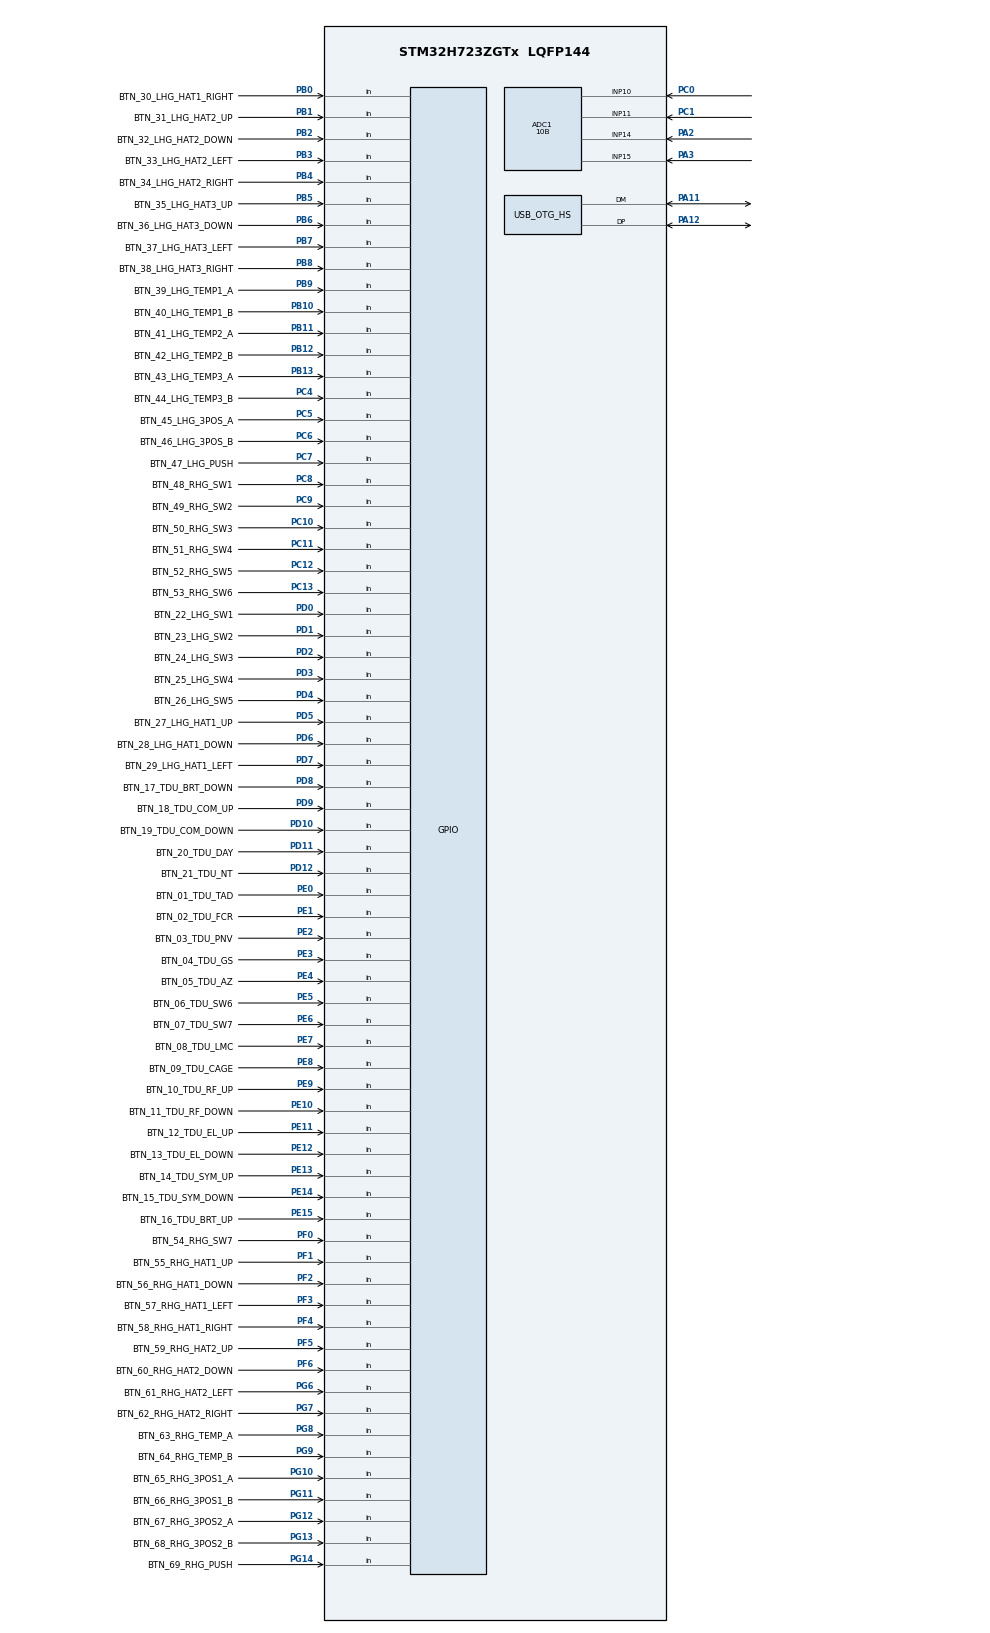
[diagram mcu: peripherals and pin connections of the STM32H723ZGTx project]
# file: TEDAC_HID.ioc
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ADC1.Channel-0\#ChannelRegularConversion=ADC_CHANNEL_3
ADC1.Channel-1\#ChannelRegularConversion=ADC_CHANNEL_7
ADC1.Channel-2\#ChannelRegularConversion=ADC_CHANNEL_14
ADC1.Channel-3\#ChannelRegularConversion=ADC_CHANNEL_15
ADC1.Channel-4\#ChannelRegularConversion=ADC_CHANNEL_10
ADC1.Channel-5\#ChannelRegularConversion=ADC_CHANNEL_11
ADC1.ClockPrescaler=ADC_CLOCK_ASYNC_DIV2
ADC1.ContinuousConvMode=ENABLE
ADC1.EOCSelection=ADC_EOC_SEQ_CONV
ADC1.ConversionDataManagement=ADC_CONVERSIONDATA_DMA_CIRCULAR
ADC1.Overrun=ADC_OVR_DATA_OVERWRITTEN
ADC1.NbrOfConversionFlag=6
ADC1.Rank-0\#ChannelRegularConversion=1
ADC1.Rank-1\#ChannelRegularConversion=2
ADC1.Rank-2\#ChannelRegularConversion=3
ADC1.Rank-3\#ChannelRegularConversion=4
ADC1.Rank-4\#ChannelRegularConversion=5
ADC1.Rank-5\#ChannelRegularConversion=6
ADC1.Resolution=ADC_RESOLUTION_10B
ADC1.ScanConvMode=ADC_SCAN_ENABLE
ADC1.SamplingTime-0\#ChannelRegularConversion=ADC_SAMPLETIME_387CYCLES_5
ADC1.SamplingTime-1\#ChannelRegularConversion=ADC_SAMPLETIME_387CYCLES_5
ADC1.SamplingTime-2\#ChannelRegularConversion=ADC_SAMPLETIME_387CYCLES_5
ADC1.SamplingTime-3\#ChannelRegularConversion=ADC_SAMPLETIME_387CYCLES_5
ADC1.SamplingTime-4\#ChannelRegularConversion=ADC_SAMPLETIME_387CYCLES_5
ADC1.SamplingTime-5\#ChannelRegularConversion=ADC_SAMPLETIME_387CYCLES_5
ADC1.master=1
CORTEX_M7.default_mode_Activation=1
Dma.ADC1.0.Direction=DMA_PERIPH_TO_MEMORY
Dma.ADC1.0.EventEnable=DISABLE
Dma.ADC1.0.FIFOMode=DMA_FIFOMODE_DISABLE
Dma.ADC1.0.Instance=DMA1_Stream0
Dma.ADC1.0.MemDataAlignment=DMA_MDATAALIGN_HALFWORD
Dma.ADC1.0.MemInc=DMA_MINC_ENABLE
Dma.ADC1.0.Mode=DMA_CIRCULAR
Dma.ADC1.0.PeriphDataAlignment=DMA_PDATAALIGN_HALFWORD
Dma.ADC1.0.PeriphInc=DMA_PINC_DISABLE
Dma.ADC1.0.Polarity=HAL_DMAMUX_REQ_GEN_RISING
Dma.ADC1.0.Priority=DMA_PRIORITY_LOW
Dma.ADC1.0.RequestNumber=1
Dma.ADC1.0.SignalID=NONE
Dma.ADC1.0.SyncEnable=DISABLE
Dma.ADC1.0.SyncPolarity=HAL_DMAMUX_SYNC_NO_EVENT
Dma.ADC1.0.SyncRequestNumber=1
Dma.ADC1.0.SyncSignalID=NONE
Dma.Request0=ADC1
Mcu.Family=STM32H7
Mcu.Name=STM32H723ZGTx
Mcu.Package=LQFP144
NVIC.DMA1_Stream0_IRQn=true\:0\:0\:false\:false\:true\:false\:true\:true
NVIC.OTG_HS_EP1_IN_IRQn=true\:0\:0\:false\:false\:true\:true\:true\:true
NVIC.OTG_HS_EP1_OUT_IRQn=true\:0\:0\:false\:false\:true\:true\:true\:true
NVIC.OTG_HS_IRQn=true\:0\:0\:false\:false\:true\:true\:true\:true
NVIC.PriorityGroup=NVIC_PRIORITYGROUP_4
NVIC.TIM15_IRQn=true\:0\:0\:false\:false\:true\:true\:true\:true
PA11.Mode=Device_Only_FS
PA11.Signal=USB_OTG_HS_DM
PA12.Mode=Device_Only_FS
PA12.Signal=USB_OTG_HS_DP
PA2.Signal=ADCx_INP14
PA3.Signal=ADCx_INP15
PA6.Signal=ADCx_INP3
PA7.Signal=ADCx_INP7
PB0.GPIO_Label=BTN_30_LHG_HAT1_RIGHT
PB0.GPIO_PuPd=GPIO_PULLUP
PB0.Signal=GPIO_Input
PB1.GPIO_Label=BTN_31_LHG_HAT2_UP
PB1.GPIO_PuPd=GPIO_PULLUP
PB1.Signal=GPIO_Input
PB10.GPIO_Label=BTN_40_LHG_TEMP1_B
PB10.GPIO_PuPd=GPIO_PULLUP
PB10.Signal=GPIO_Input
PB11.GPIO_Label=BTN_41_LHG_TEMP2_A
PB11.GPIO_PuPd=GPIO_PULLUP
PB11.Signal=GPIO_Input
PB12.GPIO_Label=BTN_42_LHG_TEMP2_B
PB12.GPIO_PuPd=GPIO_PULLUP
PB12.Signal=GPIO_Input
PB13.GPIO_Label=BTN_43_LHG_TEMP3_A
PB13.GPIO_PuPd=GPIO_PULLUP
PB13.Signal=GPIO_Input
PB2.GPIO_Label=BTN_32_LHG_HAT2_DOWN
PB2.GPIO_PuPd=GPIO_PULLUP
PB2.Signal=GPIO_Input
PB3(JTDO/TRACESWO).GPIO_Label=BTN_33_LHG_HAT2_LEFT
PB3(JTDO/TRACESWO).GPIO_PuPd=GPIO_PULLUP
PB3(JTDO/TRACESWO).Signal=GPIO_Input
PB4(NJTRST).GPIO_Label=BTN_34_LHG_HAT2_RIGHT
PB4(NJTRST).GPIO_PuPd=GPIO_PULLUP
PB4(NJTRST).Signal=GPIO_Input
PB5.GPIO_Label=BTN_35_LHG_HAT3_UP
PB5.GPIO_PuPd=GPIO_PULLUP
PB5.Signal=GPIO_Input
PB6.GPIO_Label=BTN_36_LHG_HAT3_DOWN
PB6.GPIO_PuPd=GPIO_PULLUP
PB6.Signal=GPIO_Input
PB7.GPIO_Label=BTN_37_LHG_HAT3_LEFT
PB7.GPIO_PuPd=GPIO_PULLUP
PB7.Signal=GPIO_Input
PB8.GPIO_Label=BTN_38_LHG_HAT3_RIGHT
PB8.GPIO_PuPd=GPIO_PULLUP
PB8.Signal=GPIO_Input
PB9.GPIO_Label=BTN_39_LHG_TEMP1_A
PB9.GPIO_PuPd=GPIO_PULLUP
PB9.Signal=GPIO_Input
PC0.Signal=ADCx_INP10
PC1.Signal=ADCx_INP11
PC10.GPIO_Label=BTN_50_RHG_SW3
PC10.GPIO_PuPd=GPIO_PULLUP
PC10.Signal=GPIO_Input
PC11.GPIO_Label=BTN_51_RHG_SW4
PC11.GPIO_PuPd=GPIO_PULLUP
PC11.Signal=GPIO_Input
PC12.GPIO_Label=BTN_52_RHG_SW5
PC12.GPIO_PuPd=GPIO_PULLUP
PC12.Signal=GPIO_Input
PC13.GPIO_Label=BTN_53_RHG_SW6
PC13.GPIO_PuPd=GPIO_PULLUP
PC13.Signal=GPIO_Input
PC4.GPIO_Label=BTN_44_LHG_TEMP3_B
PC4.GPIO_PuPd=GPIO_PULLUP
PC4.Signal=GPIO_Input
PC5.GPIO_Label=BTN_45_LHG_3POS_A
PC5.GPIO_PuPd=GPIO_PULLUP
PC5.Signal=GPIO_Input
PC6.GPIO_Label=BTN_46_LHG_3POS_B
PC6.GPIO_PuPd=GPIO_PULLUP
PC6.Signal=GPIO_Input
PC7.GPIO_Label=BTN_47_LHG_PUSH
PC7.GPIO_PuPd=GPIO_PULLUP
PC7.Signal=GPIO_Input
PC8.GPIO_Label=BTN_48_RHG_SW1
PC8.GPIO_PuPd=GPIO_PULLUP
PC8.Signal=GPIO_Input
PC9.GPIO_Label=BTN_49_RHG_SW2
PC9.GPIO_PuPd=GPIO_PULLUP
PC9.Signal=GPIO_Input
PD0.GPIO_Label=BTN_22_LHG_SW1
PD0.GPIO_PuPd=GPIO_PULLUP
PD0.Signal=GPIO_Input
PD1.GPIO_Label=BTN_23_LHG_SW2
PD1.GPIO_PuPd=GPIO_PULLUP
PD1.Signal=GPIO_Input
PD10.GPIO_Label=BTN_19_TDU_COM_DOWN
PD10.GPIO_PuPd=GPIO_PULLUP
PD10.Signal=GPIO_Input
PD11.GPIO_Label=BTN_20_TDU_DAY
PD11.GPIO_PuPd=GPIO_PULLUP
PD11.Signal=GPIO_Input
PD12.GPIO_Label=BTN_21_TDU_NT
PD12.GPIO_PuPd=GPIO_PULLUP
PD12.Signal=GPIO_Input
PD2.GPIO_Label=BTN_24_LHG_SW3
PD2.GPIO_PuPd=GPIO_PULLUP
PD2.Signal=GPIO_Input
PD3.GPIO_Label=BTN_25_LHG_SW4
PD3.GPIO_PuPd=GPIO_PULLUP
PD3.Signal=GPIO_Input
PD4.GPIO_Label=BTN_26_LHG_SW5
PD4.GPIO_PuPd=GPIO_PULLUP
PD4.Signal=GPIO_Input
PD5.GPIO_Label=BTN_27_LHG_HAT1_UP
PD5.GPIO_PuPd=GPIO_PULLUP
PD5.Signal=GPIO_Input
PD6.GPIO_Label=BTN_28_LHG_HAT1_DOWN
PD6.GPIO_PuPd=GPIO_PULLUP
PD6.Signal=GPIO_Input
PD7.GPIO_Label=BTN_29_LHG_HAT1_LEFT
PD7.GPIO_PuPd=GPIO_PULLUP
PD7.Signal=GPIO_Input
PD8.GPIO_Label=BTN_17_TDU_BRT_DOWN
PD8.GPIO_PuPd=GPIO_PULLUP
PD8.Signal=GPIO_Input
PD9.GPIO_Label=BTN_18_TDU_COM_UP
PD9.GPIO_PuPd=GPIO_PULLUP
PD9.Signal=GPIO_Input
PE0.GPIO_Label=BTN_01_TDU_TAD
PE0.GPIO_PuPd=GPIO_PULLUP
PE0.Signal=GPIO_Input
PE1.GPIO_Label=BTN_02_TDU_FCR
PE1.GPIO_PuPd=GPIO_PULLUP
PE1.Signal=GPIO_Input
PE10.GPIO_Label=BTN_11_TDU_RF_DOWN
PE10.GPIO_PuPd=GPIO_PULLUP
PE10.Signal=GPIO_Input
PE11.GPIO_Label=BTN_12_TDU_EL_UP
PE11.GPIO_PuPd=GPIO_PULLUP
PE11.Signal=GPIO_Input
PE12.GPIO_Label=BTN_13_TDU_EL_DOWN
PE12.GPIO_PuPd=GPIO_PULLUP
PE12.Signal=GPIO_Input
PE13.GPIO_Label=BTN_14_TDU_SYM_UP
PE13.GPIO_PuPd=GPIO_PULLUP
PE13.Signal=GPIO_Input
PE14.GPIO_Label=BTN_15_TDU_SYM_DOWN
PE14.GPIO_PuPd=GPIO_PULLUP
PE14.Signal=GPIO_Input
PE15.GPIO_Label=BTN_16_TDU_BRT_UP
PE15.GPIO_PuPd=GPIO_PULLUP
PE15.Signal=GPIO_Input
PE2.GPIO_Label=BTN_03_TDU_PNV
PE2.GPIO_PuPd=GPIO_PULLUP
PE2.Signal=GPIO_Input
PE3.GPIO_Label=BTN_04_TDU_GS
PE3.GPIO_PuPd=GPIO_PULLUP
PE3.Signal=GPIO_Input
PE4.GPIO_Label=BTN_05_TDU_AZ
PE4.GPIO_PuPd=GPIO_PULLUP
PE4.Signal=GPIO_Input
PE5.GPIO_Label=BTN_06_TDU_SW6
PE5.GPIO_PuPd=GPIO_PULLUP
PE5.Signal=GPIO_Input
PE6.GPIO_Label=BTN_07_TDU_SW7
PE6.GPIO_PuPd=GPIO_PULLUP
PE6.Signal=GPIO_Input
PE7.GPIO_Label=BTN_08_TDU_LMC
PE7.GPIO_PuPd=GPIO_PULLUP
PE7.Signal=GPIO_Input
PE8.GPIO_Label=BTN_09_TDU_CAGE
PE8.GPIO_PuPd=GPIO_PULLUP
PE8.Signal=GPIO_Input
PE9.GPIO_Label=BTN_10_TDU_RF_UP
PE9.GPIO_PuPd=GPIO_PULLUP
PE9.Signal=GPIO_Input
PF0.GPIO_Label=BTN_54_RHG_SW7
PF0.GPIO_PuPd=GPIO_PULLUP
PF0.Signal=GPIO_Input
PF1.GPIO_Label=BTN_55_RHG_HAT1_UP
PF1.GPIO_PuPd=GPIO_PULLUP
PF1.Signal=GPIO_Input
PF2.GPIO_Label=BTN_56_RHG_HAT1_DOWN
PF2.GPIO_PuPd=GPIO_PULLUP
PF2.Signal=GPIO_Input
PF3.GPIO_Label=BTN_57_RHG_HAT1_LEFT
PF3.GPIO_PuPd=GPIO_PULLUP
PF3.Signal=GPIO_Input
PF4.GPIO_Label=BTN_58_RHG_HAT1_RIGHT
PF4.GPIO_PuPd=GPIO_PULLUP
PF4.Signal=GPIO_Input
PF5.GPIO_Label=BTN_59_RHG_HAT2_UP
PF5.GPIO_PuPd=GPIO_PULLUP
PF5.Signal=GPIO_Input
PF6.GPIO_Label=BTN_60_RHG_HAT2_DOWN
PF6.GPIO_PuPd=GPIO_PULLUP
PF6.Signal=GPIO_Input
PG10.GPIO_Label=BTN_65_RHG_3POS1_A
PG10.GPIO_PuPd=GPIO_PULLUP
PG10.Signal=GPIO_Input
PG11.GPIO_Label=BTN_66_RHG_3POS1_B
PG11.GPIO_PuPd=GPIO_PULLUP
PG11.Signal=GPIO_Input
PG12.GPIO_Label=BTN_67_RHG_3POS2_A
PG12.GPIO_PuPd=GPIO_PULLUP
PG12.Signal=GPIO_Input
PG13.GPIO_Label=BTN_68_RHG_3POS2_B
PG13.GPIO_PuPd=GPIO_PULLUP
PG13.Signal=GPIO_Input
PG14.GPIO_Label=BTN_69_RHG_PUSH
PG14.GPIO_PuPd=GPIO_PULLUP
PG14.Signal=GPIO_Input
PG6.GPIO_Label=BTN_61_RHG_HAT2_LEFT
PG6.GPIO_PuPd=GPIO_PULLUP
PG6.Signal=GPIO_Input
PG7.GPIO_Label=BTN_62_RHG_HAT2_RIGHT
PG7.GPIO_PuPd=GPIO_PULLUP
PG7.Signal=GPIO_Input
PG8.GPIO_Label=BTN_63_RHG_TEMP_A
PG8.GPIO_PuPd=GPIO_PULLUP
PG8.Signal=GPIO_Input
PG9.GPIO_Label=BTN_64_RHG_TEMP_B
PG9.GPIO_PuPd=GPIO_PULLUP
PG9.Signal=GPIO_Input
PH0-OSC_IN.Mode=HSE-External-Oscillator
PH0-OSC_IN.Signal=RCC_OSC_IN
PH1-OSC_OUT.Mode=HSE-External-Oscillator
PH1-OSC_OUT.Signal=RCC_OSC_OUT
ProjectManager.HeapSize=0x200
ProjectManager.StackSize=0x400
ProjectManager.TargetToolchain=STM32CubeIDE
RCC.ADCFreq_Value=20000000
RCC.APB1Freq_Value=137500000
RCC.APB2Freq_Value=137500000
RCC.APB3Freq_Value=137500000
RCC.APB4Freq_Value=137500000
RCC.CortexFreq_Value=275000000
RCC.D1PPRE=RCC_APB3_DIV2
RCC.D2PPRE1=RCC_APB1_DIV2
RCC.D2PPRE2=RCC_APB2_DIV2
RCC.D3PPRE=RCC_APB4_DIV2
RCC.DIVM1=2
RCC.DIVM2=2
RCC.DIVM3=2
RCC.DIVN1=22
RCC.DIVN2=40
RCC.DIVN3=24
RCC.DIVP1=1
RCC.DIVP2=25
RCC.DIVQ1=5
RCC.DIVQ3=5
RCC.HCLKFreq_Value=275000000
RCC.PLL2FRACN=0
RCC.PLL3FRACN=0
RCC.PLLFRACN=0
RCC.PLLSourceVirtual=RCC_PLLSOURCE_HSE
RCC.SYSCLKFreq_VALUE=275000000
RCC.SYSCLKSource=RCC_SYSCLKSOURCE_PLLCLK
RCC.USBCLockSelection=RCC_USBCLKSOURCE_HSI48
RCC.USBFreq_Value=48000000
SH.ADCx_INP10.0=ADC1_INP10,IN10-Single-Ended
SH.ADCx_INP11.0=ADC1_INP11,IN11-Single-Ended
SH.ADCx_INP14.0=ADC1_INP14,IN14-Single-Ended
SH.ADCx_INP15.0=ADC1_INP15,IN15-Single-Ended
SH.ADCx_INP3.0=ADC1_INP3
SH.ADCx_INP7.0=ADC1_INP7
TIM15.Period=100-1
TIM15.Prescaler=2750-1
TIM15.TIM_MasterOutputTrigger=TIM_TRGO_UPDATE
USB_DEVICE.CLASS_NAME_HS=CUSTOM_HID
USB_DEVICE.MANUFACTURER_STRING=DIPRE
USB_DEVICE.PRODUCT_STRING_CUSTOMHID_HS=TEDAC AH-64D
USB_DEVICE.USBD_CUSTOM_HID_REPORT_DESC_SIZE=0x37
USB_DEVICE.VirtualMode=CustomHid
USB_DEVICE.VirtualModeHS=Custom_Hid_HS
USB_OTG_HS.VirtualMode-Device_Only_FS=Device_Only_FS
VP_MEMORYMAP_VS_MEMORYMAP.Mode=CurAppReg
VP_RCC_USB.Mode=USB_HS
VP_TIM15_VS_ClockSourceINT.Mode=Internal
VP_USB_DEVICE_VS_USB_DEVICE_CUSTOM_HID_HS.Mode=CUSTOM_HID_HS
board=custom

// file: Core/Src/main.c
/* USER CODE BEGIN Header */
/**
  ******************************************************************************
  * @file           : main.c
  * @brief          : Main program body
  ******************************************************************************
  * @attention
  *
  * Copyright (c) 2026 STMicroelectronics.
  * All rights reserved.
  *
  * This software is licensed under terms that can be found in the LICENSE file
  * in the root directory of this software component.
  * If no LICENSE file comes with this software, it is provided AS-IS.
  *
  ******************************************************************************
  */
/* USER CODE END Header */
#include "main.h"
#include "usb_device.h"

/* USER CODE BEGIN Includes */
#include "usbd_custom_hid_if.h"
/* USER CODE END Includes */

ADC_HandleTypeDef hadc1;
DMA_HandleTypeDef hdma_adc1;

TIM_HandleTypeDef htim15;

/* USER CODE BEGIN PV */
/*
 * CRITICAL: adc_buf MUST be in D2 SRAM (0x30000000) because DMA1 lives in the
 * D2 bus-matrix domain and CANNOT access D1 AXI SRAM (0x24000000 / RAM_D1).
 * Without this attribute the linker places it in .bss → RAM_D1 → DMA writes go nowhere.
 */
volatile uint16_t adc_buf[6] __attribute__((section(".RAM_D2")));
/* USER CODE END PV */

void SystemClock_Config(void);
static void MPU_Config(void);
static void MX_GPIO_Init(void);
static void MX_DMA_Init(void);
static void MX_ADC1_Init(void);
static void MX_TIM15_Init(void);

int main(void)
{

  /* MPU Configuration--------------------------------------------------------*/
  MPU_Config();

  /* MCU Configuration--------------------------------------------------------*/

  /* Reset of all peripherals, Initializes the Flash interface and the Systick. */
  HAL_Init();

  /* Configure the system clock */
  SystemClock_Config();

  /* Initialize all configured peripherals */
  MX_GPIO_Init();
  MX_DMA_Init();
  MX_ADC1_Init();
  MX_TIM15_Init();
  MX_USB_DEVICE_Init();
  /* USER CODE BEGIN 2 */
  if (HAL_ADCEx_Calibration_Start(&hadc1, ADC_CALIB_OFFSET, ADC_SINGLE_ENDED) != HAL_OK)
  {
    Error_Handler();
  }

  if (HAL_ADC_Start_DMA(&hadc1, (uint32_t*)adc_buf, 6) != HAL_OK)
  {
    Error_Handler();
  }

  if (HAL_TIM_Base_Start_IT(&htim15) != HAL_OK)
  {
    Error_Handler();
  }
  /* USER CODE END 2 */

  /* Infinite loop */
  while (1)
  {

  }
}

void SystemClock_Config(void)
{
  RCC_OscInitTypeDef RCC_OscInitStruct = {0};
  RCC_ClkInitTypeDef RCC_ClkInitStruct = {0};
  RCC_CRSInitTypeDef RCC_CRSInitStruct = {0};

  /** Supply configuration update enable
  */
  HAL_PWREx_ConfigSupply(PWR_LDO_SUPPLY);

  /** Configure the main internal regulator output voltage
  */
  __HAL_PWR_VOLTAGESCALING_CONFIG(PWR_REGULATOR_VOLTAGE_SCALE0);

  while(!__HAL_PWR_GET_FLAG(PWR_FLAG_VOSRDY)) {}

  /** Initializes the RCC Oscillators according to the specified parameters
  * in the RCC_OscInitTypeDef structure.
  */
  RCC_OscInitStruct.OscillatorType = RCC_OSCILLATORTYPE_HSI48|RCC_OSCILLATORTYPE_HSE;
  RCC_OscInitStruct.HSEState = RCC_HSE_ON;
  RCC_OscInitStruct.HSI48State = RCC_HSI48_ON;
  RCC_OscInitStruct.PLL.PLLState = RCC_PLL_ON;
  RCC_OscInitStruct.PLL.PLLSource = RCC_PLLSOURCE_HSE;
  RCC_OscInitStruct.PLL.PLLM = 2;
  RCC_OscInitStruct.PLL.PLLN = 22;
  RCC_OscInitStruct.PLL.PLLP = 1;
  RCC_OscInitStruct.PLL.PLLQ = 5;
  RCC_OscInitStruct.PLL.PLLR = 2;
  RCC_OscInitStruct.PLL.PLLRGE = RCC_PLL1VCIRANGE_3;
  RCC_OscInitStruct.PLL.PLLVCOSEL = RCC_PLL1VCOWIDE;
  RCC_OscInitStruct.PLL.PLLFRACN = 0;
  if (HAL_RCC_OscConfig(&RCC_OscInitStruct) != HAL_OK)
  {
    Error_Handler();
  }

  /** Initializes the CPU, AHB and APB buses clocks
  */
  RCC_ClkInitStruct.ClockType = RCC_CLOCKTYPE_HCLK|RCC_CLOCKTYPE_SYSCLK
                              |RCC_CLOCKTYPE_PCLK1|RCC_CLOCKTYPE_PCLK2
                              |RCC_CLOCKTYPE_D3PCLK1|RCC_CLOCKTYPE_D1PCLK1;
  RCC_ClkInitStruct.SYSCLKSource = RCC_SYSCLKSOURCE_PLLCLK;
  RCC_ClkInitStruct.SYSCLKDivider = RCC_SYSCLK_DIV1;
  RCC_ClkInitStruct.AHBCLKDivider = RCC_HCLK_DIV1;
  RCC_ClkInitStruct.APB3CLKDivider = RCC_APB3_DIV2;
  RCC_ClkInitStruct.APB1CLKDivider = RCC_APB1_DIV2;
  RCC_ClkInitStruct.APB2CLKDivider = RCC_APB2_DIV2;
  RCC_ClkInitStruct.APB4CLKDivider = RCC_APB4_DIV2;

  if (HAL_RCC_ClockConfig(&RCC_ClkInitStruct, FLASH_LATENCY_3) != HAL_OK)
  {
    Error_Handler();
  }

  /** Enable the SYSCFG APB clock
  */
  __HAL_RCC_CRS_CLK_ENABLE();

  /** Configures CRS
  */
  RCC_CRSInitStruct.Prescaler = RCC_CRS_SYNC_DIV1;
  RCC_CRSInitStruct.Source = RCC_CRS_SYNC_SOURCE_USB2;
  RCC_CRSInitStruct.Polarity = RCC_CRS_SYNC_POLARITY_RISING;
  RCC_CRSInitStruct.ReloadValue = __HAL_RCC_CRS_RELOADVALUE_CALCULATE(48000000,1000);
  RCC_CRSInitStruct.ErrorLimitValue = 34;
  RCC_CRSInitStruct.HSI48CalibrationValue = 32;

  HAL_RCCEx_CRSConfig(&RCC_CRSInitStruct);
}

static void MX_ADC1_Init(void)
{

  ADC_MultiModeTypeDef multimode = {0};
  ADC_ChannelConfTypeDef sConfig = {0};

  /** Common config
  */
  hadc1.Instance = ADC1;
  hadc1.Init.ClockPrescaler = ADC_CLOCK_ASYNC_DIV2;
  hadc1.Init.Resolution = ADC_RESOLUTION_10B;
  hadc1.Init.ScanConvMode = ADC_SCAN_ENABLE;        /* 6 channels */
  hadc1.Init.EOCSelection = ADC_EOC_SEQ_CONV;       /* end of sequence */
  hadc1.Init.LowPowerAutoWait = DISABLE;
  hadc1.Init.ContinuousConvMode = ENABLE;
  hadc1.Init.NbrOfConversion = 6;
  hadc1.Init.DiscontinuousConvMode = DISABLE;
  hadc1.Init.ExternalTrigConv = ADC_SOFTWARE_START;
  hadc1.Init.ExternalTrigConvEdge = ADC_EXTERNALTRIGCONVEDGE_NONE;
  hadc1.Init.ConversionDataManagement = ADC_CONVERSIONDATA_DMA_CIRCULAR;
  hadc1.Init.Overrun = ADC_OVR_DATA_OVERWRITTEN;
  hadc1.Init.LeftBitShift = ADC_LEFTBITSHIFT_NONE;
  hadc1.Init.OversamplingMode = DISABLE;
  hadc1.Init.Oversampling.Ratio = 1;
  if (HAL_ADC_Init(&hadc1) != HAL_OK)
  {
    Error_Handler();
  }

  /** Configure the ADC multi-mode
  */
  multimode.Mode = ADC_MODE_INDEPENDENT;
  if (HAL_ADCEx_MultiModeConfigChannel(&hadc1, &multimode) != HAL_OK)
  {
    Error_Handler();
  }

  /* Rank 1: IN3  = PA6  = X axis */
  sConfig.Channel = ADC_CHANNEL_3;
  sConfig.Rank = ADC_REGULAR_RANK_1;
  sConfig.SamplingTime = ADC_SAMPLETIME_387CYCLES_5;
  sConfig.SingleDiff = ADC_SINGLE_ENDED;
  sConfig.OffsetNumber = ADC_OFFSET_NONE;
  sConfig.Offset = 0;
  sConfig.OffsetSignedSaturation = DISABLE;
  if (HAL_ADC_ConfigChannel(&hadc1, &sConfig) != HAL_OK)
  {
    Error_Handler();
  }

  /* Rank 2: IN7  = PA7  = Y axis */
  sConfig.Channel = ADC_CHANNEL_7;
  sConfig.Rank = ADC_REGULAR_RANK_2;
  if (HAL_ADC_ConfigChannel(&hadc1, &sConfig) != HAL_OK)
  {
    Error_Handler();
  }

  /* Rank 3: IN14 = PA2  = Z axis */
  sConfig.Channel = ADC_CHANNEL_14;
  sConfig.Rank = ADC_REGULAR_RANK_3;
  if (HAL_ADC_ConfigChannel(&hadc1, &sConfig) != HAL_OK)
  {
    Error_Handler();
  }

  /* Rank 4: IN15 = PA3  = Rx axis */
  sConfig.Channel = ADC_CHANNEL_15;
  sConfig.Rank = ADC_REGULAR_RANK_4;
  if (HAL_ADC_ConfigChannel(&hadc1, &sConfig) != HAL_OK)
  {
    Error_Handler();
  }

  /* Rank 5: IN10 = PC0  = Ry axis */
  sConfig.Channel = ADC_CHANNEL_10;
  sConfig.Rank = ADC_REGULAR_RANK_5;
  if (HAL_ADC_ConfigChannel(&hadc1, &sConfig) != HAL_OK)
  {
    Error_Handler();
  }

  /* Rank 6: IN11 = PC1  = Rz axis */
  sConfig.Channel = ADC_CHANNEL_11;
  sConfig.Rank = ADC_REGULAR_RANK_6;
  if (HAL_ADC_ConfigChannel(&hadc1, &sConfig) != HAL_OK)
  {
    Error_Handler();
  }

  /* USER CODE BEGIN ADC1_Init 2 */

  /*
   * STM32H7 CRITICAL: PCSEL register must pre-select all channels before
   * starting conversions. Without this, the ADC samples floating inputs.
   * Bits correspond directly to channel numbers (bit N = channel N).
   */
  /* On STM32H723, ADC_TypeDef names this field PCSEL_RES0 (shared with ADC3
   * reservation), but it is the PCSEL register at offset 0x1C for ADC1/2. */
  ADC1->PCSEL_RES0 |= (1UL << 3)  /* IN3  = PA6 */
                    | (1UL << 7)  /* IN7  = PA7 */
                    | (1UL << 10) /* IN10 = PC0 */
                    | (1UL << 11) /* IN11 = PC1 */
                    | (1UL << 14) /* IN14 = PA2 */
                    | (1UL << 15);/* IN15 = PA3 */

  /* USER CODE END ADC1_Init 2 */

}

static void MX_TIM15_Init(void)
{

  TIM_ClockConfigTypeDef sClockSourceConfig = {0};
  TIM_MasterConfigTypeDef sMasterConfig = {0};

  htim15.Instance = TIM15;
  htim15.Init.Prescaler = 2750-1;
  htim15.Init.CounterMode = TIM_COUNTERMODE_UP;
  htim15.Init.Period = 100-1;
  htim15.Init.ClockDivision = TIM_CLOCKDIVISION_DIV1;
  htim15.Init.RepetitionCounter = 0;
  htim15.Init.AutoReloadPreload = TIM_AUTORELOAD_PRELOAD_DISABLE;
  if (HAL_TIM_Base_Init(&htim15) != HAL_OK)
  {
    Error_Handler();
  }
  sClockSourceConfig.ClockSource = TIM_CLOCKSOURCE_INTERNAL;
  if (HAL_TIM_ConfigClockSource(&htim15, &sClockSourceConfig) != HAL_OK)
  {
    Error_Handler();
  }
  sMasterConfig.MasterOutputTrigger = TIM_TRGO_UPDATE;
  sMasterConfig.MasterSlaveMode = TIM_MASTERSLAVEMODE_DISABLE;
  if (HAL_TIMEx_MasterConfigSynchronization(&htim15, &sMasterConfig) != HAL_OK)
  {
    Error_Handler();
  }

}

static void MX_DMA_Init(void)
{

  /* DMA controller clock enable */
  __HAL_RCC_DMA1_CLK_ENABLE();

  /* DMA interrupt init */
  /* DMA1_Stream0_IRQn interrupt configuration */
  HAL_NVIC_SetPriority(DMA1_Stream0_IRQn, 0, 0);
  HAL_NVIC_EnableIRQ(DMA1_Stream0_IRQn);

}

static void MX_GPIO_Init(void)
{
  GPIO_InitTypeDef GPIO_InitStruct = {0};

  /* GPIO Ports Clock Enable */
  __HAL_RCC_GPIOE_CLK_ENABLE();
  __HAL_RCC_GPIOC_CLK_ENABLE();
  __HAL_RCC_GPIOF_CLK_ENABLE();
  __HAL_RCC_GPIOH_CLK_ENABLE();
  __HAL_RCC_GPIOA_CLK_ENABLE();
  __HAL_RCC_GPIOB_CLK_ENABLE();
  __HAL_RCC_GPIOD_CLK_ENABLE();
  __HAL_RCC_GPIOG_CLK_ENABLE();

  /*Configure GPIO pins : BTN_03_TDU_PNV_Pin BTN_04_TDU_GS_Pin BTN_05_TDU_AZ_Pin BTN_06_TDU_SW6_Pin
                           BTN_07_TDU_SW7_Pin BTN_08_TDU_LMC_Pin BTN_09_TDU_CAGE_Pin BTN_10_TDU_RF_UP_Pin
                           BTN_11_TDU_RF_DOWN_Pin BTN_12_TDU_EL_UP_Pin BTN_13_TDU_EL_DOWN_Pin BTN_14_TDU_SYM_UP_Pin
                           BTN_15_TDU_SYM_DOWN_Pin BTN_16_TDU_BRT_UP_Pin BTN_01_TDU_TAD_Pin BTN_02_TDU_FCR_Pin */
  GPIO_InitStruct.Pin = BTN_03_TDU_PNV_Pin|BTN_04_TDU_GS_Pin|BTN_05_TDU_AZ_Pin|BTN_06_TDU_SW6_Pin
                          |BTN_07_TDU_SW7_Pin|BTN_08_TDU_LMC_Pin|BTN_09_TDU_CAGE_Pin|BTN_10_TDU_RF_UP_Pin
                          |BTN_11_TDU_RF_DOWN_Pin|BTN_12_TDU_EL_UP_Pin|BTN_13_TDU_EL_DOWN_Pin|BTN_14_TDU_SYM_UP_Pin
                          |BTN_15_TDU_SYM_DOWN_Pin|BTN_16_TDU_BRT_UP_Pin|BTN_01_TDU_TAD_Pin|BTN_02_TDU_FCR_Pin;
  GPIO_InitStruct.Mode = GPIO_MODE_INPUT;
  GPIO_InitStruct.Pull = GPIO_PULLUP;
  HAL_GPIO_Init(GPIOE, &GPIO_InitStruct);

  /*Configure GPIO pins : BTN_53_RHG_SW6_Pin BTN_44_LHG_TEMP3_B_Pin BTN_45_LHG_3POS_A_Pin BTN_46_LHG_3POS_B_Pin
                           BTN_47_LHG_PUSH_Pin BTN_50_RHG_SW3_Pin BTN_51_RHG_SW4_Pin BTN_52_RHG_SW5_Pin */
  GPIO_InitStruct.Pin = BTN_53_RHG_SW6_Pin|BTN_44_LHG_TEMP3_B_Pin|BTN_45_LHG_3POS_A_Pin|BTN_46_LHG_3POS_B_Pin
                          |BTN_47_LHG_PUSH_Pin|BTN_50_RHG_SW3_Pin
                          |BTN_51_RHG_SW4_Pin|BTN_52_RHG_SW5_Pin;
  GPIO_InitStruct.Mode = GPIO_MODE_INPUT;
  GPIO_InitStruct.Pull = GPIO_PULLUP;
  HAL_GPIO_Init(GPIOC, &GPIO_InitStruct);

  /*Configure GPIO pins : BTN_54_RHG_SW7_Pin BTN_55_RHG_HAT1_UP_Pin BTN_56_RHG_HAT1_DOWN_Pin BTN_57_RHG_HAT1_LEFT_Pin
                           BTN_58_RHG_HAT1_RIGHT_Pin BTN_59_RHG_HAT2_UP_Pin BTN_60_RHG_HAT2_DOWN_Pin
                           BTN_71_SPARE1_Pin BTN_72_SPARE2_Pin */
  GPIO_InitStruct.Pin = BTN_54_RHG_SW7_Pin|BTN_55_RHG_HAT1_UP_Pin|BTN_56_RHG_HAT1_DOWN_Pin|BTN_57_RHG_HAT1_LEFT_Pin
                          |BTN_58_RHG_HAT1_RIGHT_Pin|BTN_59_RHG_HAT2_UP_Pin|BTN_60_RHG_HAT2_DOWN_Pin
                          |BTN_71_SPARE1_Pin|BTN_72_SPARE2_Pin;
  GPIO_InitStruct.Mode = GPIO_MODE_INPUT;
  GPIO_InitStruct.Pull = GPIO_PULLUP;
  HAL_GPIO_Init(GPIOF, &GPIO_InitStruct);

  /*Configure GPIO pins : BTN_30_LHG_HAT1_RIGHT_Pin BTN_31_LHG_HAT2_UP_Pin BTN_32_LHG_HAT2_DOWN_Pin BTN_40_LHG_TEMP1_B_Pin
                           BTN_41_LHG_TEMP2_A_Pin BTN_42_LHG_TEMP2_B_Pin BTN_43_LHG_TEMP3_A_Pin BTN_33_LHG_HAT2_LEFT_Pin
                           BTN_34_LHG_HAT2_RIGHT_Pin BTN_35_LHG_HAT3_UP_Pin BTN_36_LHG_HAT3_DOWN_Pin BTN_37_LHG_HAT3_LEFT_Pin
                           BTN_38_LHG_HAT3_RIGHT_Pin BTN_39_LHG_TEMP1_A_Pin BTN_48_RHG_SW1_Pin BTN_49_RHG_SW2_Pin */
  GPIO_InitStruct.Pin = BTN_30_LHG_HAT1_RIGHT_Pin|BTN_31_LHG_HAT2_UP_Pin|BTN_32_LHG_HAT2_DOWN_Pin|BTN_40_LHG_TEMP1_B_Pin
                          |BTN_41_LHG_TEMP2_A_Pin|BTN_42_LHG_TEMP2_B_Pin|BTN_43_LHG_TEMP3_A_Pin|BTN_33_LHG_HAT2_LEFT_Pin
                          |BTN_34_LHG_HAT2_RIGHT_Pin|BTN_35_LHG_HAT3_UP_Pin|BTN_36_LHG_HAT3_DOWN_Pin|BTN_37_LHG_HAT3_LEFT_Pin
                          |BTN_38_LHG_HAT3_RIGHT_Pin|BTN_39_LHG_TEMP1_A_Pin|BTN_48_RHG_SW1_Pin|BTN_49_RHG_SW2_Pin;
  GPIO_InitStruct.Mode = GPIO_MODE_INPUT;
  GPIO_InitStruct.Pull = GPIO_PULLUP;
  HAL_GPIO_Init(GPIOB, &GPIO_InitStruct);

  /*Configure GPIO pins : BTN_17_TDU_BRT_DOWN_Pin BTN_18_TDU_COM_UP_Pin BTN_19_TDU_COM_DOWN_Pin BTN_20_TDU_DAY_Pin
                           BTN_21_TDU_NT_Pin BTN_22_LHG_SW1_Pin BTN_23_LHG_SW2_Pin BTN_24_LHG_SW3_Pin
                           BTN_25_LHG_SW4_Pin BTN_26_LHG_SW5_Pin BTN_27_LHG_HAT1_UP_Pin BTN_28_LHG_HAT1_DOWN_Pin
                           BTN_29_LHG_HAT1_LEFT_Pin BTN_73_LHG_TRIG_POS1_Pin BTN_74_LHG_TRIG_POS2_Pin */
  GPIO_InitStruct.Pin = BTN_17_TDU_BRT_DOWN_Pin|BTN_18_TDU_COM_UP_Pin|BTN_19_TDU_COM_DOWN_Pin|BTN_20_TDU_DAY_Pin
                          |BTN_21_TDU_NT_Pin|BTN_22_LHG_SW1_Pin|BTN_23_LHG_SW2_Pin|BTN_24_LHG_SW3_Pin
                          |BTN_25_LHG_SW4_Pin|BTN_26_LHG_SW5_Pin|BTN_27_LHG_HAT1_UP_Pin|BTN_28_LHG_HAT1_DOWN_Pin
                          |BTN_29_LHG_HAT1_LEFT_Pin|BTN_73_LHG_TRIG_POS1_Pin|BTN_74_LHG_TRIG_POS2_Pin;
  GPIO_InitStruct.Mode = GPIO_MODE_INPUT;
  GPIO_InitStruct.Pull = GPIO_PULLUP;
  HAL_GPIO_Init(GPIOD, &GPIO_InitStruct);

  /*Configure GPIO pins : BTN_61_RHG_HAT2_LEFT_Pin BTN_62_RHG_HAT2_RIGHT_Pin BTN_63_RHG_TEMP_A_Pin BTN_64_RHG_TEMP_B_Pin
                           BTN_65_RHG_3POS1_A_Pin BTN_66_RHG_3POS1_B_Pin BTN_67_RHG_3POS2_A_Pin BTN_68_RHG_3POS2_B_Pin
                           BTN_69_RHG_PUSH_Pin BTN_70_TDU_OFF_Pin BTN_75_RHG_SW8_Pin BTN_76_RHG_SW9_Pin */
  GPIO_InitStruct.Pin = BTN_61_RHG_HAT2_LEFT_Pin|BTN_62_RHG_HAT2_RIGHT_Pin|BTN_63_RHG_TEMP_A_Pin|BTN_64_RHG_TEMP_B_Pin
                          |BTN_65_RHG_3POS1_A_Pin|BTN_66_RHG_3POS1_B_Pin|BTN_67_RHG_3POS2_A_Pin|BTN_68_RHG_3POS2_B_Pin
                          |BTN_69_RHG_PUSH_Pin|BTN_70_TDU_OFF_Pin|BTN_75_RHG_SW8_Pin|BTN_76_RHG_SW9_Pin;
  GPIO_InitStruct.Mode = GPIO_MODE_INPUT;
  GPIO_InitStruct.Pull = GPIO_PULLUP;
  HAL_GPIO_Init(GPIOG, &GPIO_InitStruct);

}

/* USER CODE BEGIN 4 */
void HAL_TIM_PeriodElapsedCallback(TIM_HandleTypeDef *htim)
{
  if (htim->Instance == TIM15)
  {
    JOYSTICK_SendReport();
  }
}

/*
 * DCache invalidation callbacks — belt-and-suspenders defence.
 * RAM_D2 is already marked non-cacheable by MPU_Config (Region 1),
 * so these are normally no-ops. If the MPU were ever misconfigured,
 * these callbacks ensure the CPU sees fresh DMA data.
 */
void HAL_ADC_ConvCpltCallback(ADC_HandleTypeDef *hadc)
{
  if (hadc->Instance == ADC1)
  {
    SCB_InvalidateDCache_by_Addr((uint32_t *)adc_buf, sizeof(adc_buf));
  }
}

void HAL_ADC_ConvHalfCpltCallback(ADC_HandleTypeDef *hadc)
{
  if (hadc->Instance == ADC1)
  {
    SCB_InvalidateDCache_by_Addr((uint32_t *)adc_buf, sizeof(adc_buf));
  }
}
/* USER CODE END 4 */

 /* MPU Configuration */

void MPU_Config(void)
{
  MPU_Region_InitTypeDef MPU_InitStruct = {0};

  /* Disables the MPU */
  HAL_MPU_Disable();

  /* Region 0: default — whole 4GB no-access background region */
  MPU_InitStruct.Enable = MPU_REGION_ENABLE;
  MPU_InitStruct.Number = MPU_REGION_NUMBER0;
  MPU_InitStruct.BaseAddress = 0x0;
  MPU_InitStruct.Size = MPU_REGION_SIZE_4GB;
  MPU_InitStruct.SubRegionDisable = 0x87;
  MPU_InitStruct.TypeExtField = MPU_TEX_LEVEL0;
  MPU_InitStruct.AccessPermission = MPU_REGION_NO_ACCESS;
  MPU_InitStruct.DisableExec = MPU_INSTRUCTION_ACCESS_DISABLE;
  MPU_InitStruct.IsShareable = MPU_ACCESS_SHAREABLE;
  MPU_InitStruct.IsCacheable = MPU_ACCESS_NOT_CACHEABLE;
  MPU_InitStruct.IsBufferable = MPU_ACCESS_NOT_BUFFERABLE;
  HAL_MPU_ConfigRegion(&MPU_InitStruct);

  /*
   * Region 1: RAM_D2 (0x30000000, 32K) — non-cacheable, non-bufferable.
   * DMA1 writes adc_buf[] here. The D-Cache must NOT cache this region or
   * the CPU will read stale values. TEX=1, C=0, B=0 = Normal, non-cacheable.
   */
  MPU_InitStruct.Enable = MPU_REGION_ENABLE;
  MPU_InitStruct.Number = MPU_REGION_NUMBER1;
  MPU_InitStruct.BaseAddress = 0x30000000;
  MPU_InitStruct.Size = MPU_REGION_SIZE_32KB;
  MPU_InitStruct.SubRegionDisable = 0x00;
  MPU_InitStruct.TypeExtField = MPU_TEX_LEVEL1;
  MPU_InitStruct.AccessPermission = MPU_REGION_FULL_ACCESS;
  MPU_InitStruct.DisableExec = MPU_INSTRUCTION_ACCESS_DISABLE;
  MPU_InitStruct.IsShareable = MPU_ACCESS_NOT_SHAREABLE;
  MPU_InitStruct.IsCacheable = MPU_ACCESS_NOT_CACHEABLE;
  MPU_InitStruct.IsBufferable = MPU_ACCESS_NOT_BUFFERABLE;
  HAL_MPU_ConfigRegion(&MPU_InitStruct);

  /* Enables the MPU */
  HAL_MPU_Enable(MPU_PRIVILEGED_DEFAULT);
}

void Error_Handler(void)
{
  __disable_irq();
  while (1)
  {
  }
}
